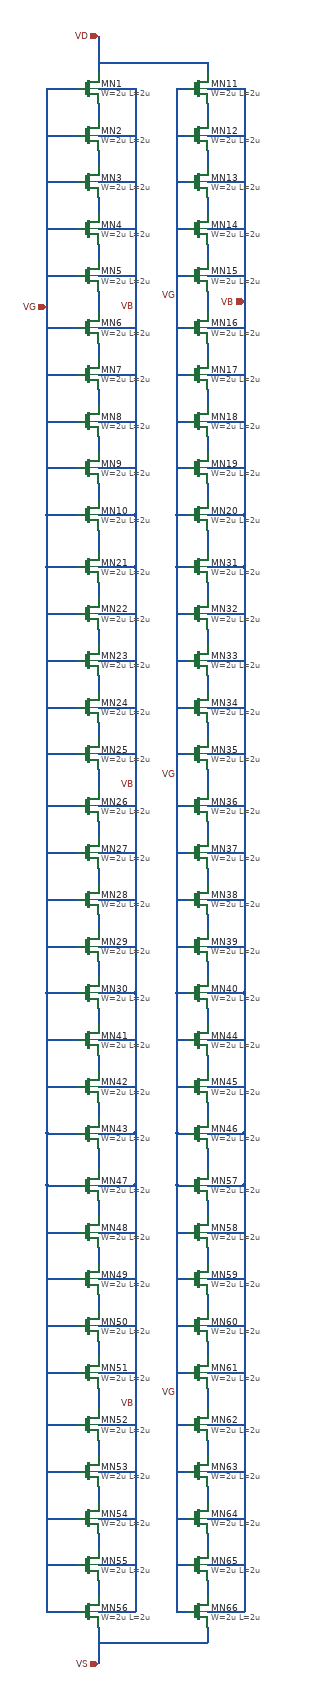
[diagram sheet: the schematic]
v {xschem version=3.4.5 file_version=1.2
}
G {}
K {}
V {}
S {}
E {}
N 0 30 0 60 {
lab=#net1}
N 0 120 0 150 {
lab=#net2}
N 0 210 0 240 {
lab=#net3}
N 0 300 0 330 {
lab=#net4}
N 0 390 0 430 {
lab=#net5}
N 0 490 0 520 {
lab=#net6}
N 0 580 0 610 {
lab=#net7}
N 0 670 0 700 {
lab=#net8}
N 0 760 0 790 {
lab=#net9}
N 0 2960 0 3030 {
lab=VS}
N 0 820 70 820 {
lab=VB}
N 70 0 70 820 {
lab=VB}
N 0 0 70 0 {
lab=VB}
N 0 90 70 90 {
lab=VB}
N 0 180 70 180 {
lab=VB}
N 0 270 70 270 {
lab=VB}
N 0 360 70 360 {
lab=VB}
N 0 460 70 460 {
lab=VB}
N 0 550 70 550 {
lab=VB}
N 0 640 70 640 {
lab=VB}
N 0 730 70 730 {
lab=VB}
N -100 0 -40 0 {
lab=VG}
N -100 0 -100 820 {
lab=VG}
N -100 820 -40 820 {
lab=VG}
N -100 730 -40 730 {
lab=VG}
N -100 640 -40 640 {
lab=VG}
N -100 550 -40 550 {
lab=VG}
N -100 460 -40 460 {
lab=VG}
N -100 360 -40 360 {
lab=VG}
N -100 270 -40 270 {
lab=VG}
N -100 180 -40 180 {
lab=VG}
N -100 90 -40 90 {
lab=VG}
N 0 -100 0 -30 {
lab=VD}
N 210 30 210 60 {
lab=#net10}
N 210 120 210 150 {
lab=#net11}
N 210 210 210 240 {
lab=#net12}
N 210 300 210 330 {
lab=#net13}
N 210 390 210 430 {
lab=#net14}
N 210 490 210 520 {
lab=#net15}
N 210 580 210 610 {
lab=#net16}
N 210 670 210 700 {
lab=#net17}
N 210 760 210 790 {
lab=#net18}
N 210 820 280 820 {
lab=VB}
N 280 0 280 820 {
lab=VB}
N 210 0 280 0 {
lab=VB}
N 210 90 280 90 {
lab=VB}
N 210 180 280 180 {
lab=VB}
N 210 270 280 270 {
lab=VB}
N 210 360 280 360 {
lab=VB}
N 210 460 280 460 {
lab=VB}
N 210 550 280 550 {
lab=VB}
N 210 640 280 640 {
lab=VB}
N 210 730 280 730 {
lab=VB}
N 150 0 170 0 {
lab=VG}
N 150 0 150 820 {
lab=VG}
N 150 820 170 820 {
lab=VG}
N 150 730 170 730 {
lab=VG}
N 150 640 170 640 {
lab=VG}
N 150 550 170 550 {
lab=VG}
N 150 460 170 460 {
lab=VG}
N 150 360 170 360 {
lab=VG}
N 150 270 170 270 {
lab=VG}
N 150 180 170 180 {
lab=VG}
N 150 90 170 90 {
lab=VG}
N 210 -50 210 -30 {
lab=VD}
N 0 -50 210 -50 {
lab=VD}
N 0 950 0 980 {
lab=#net19}
N 0 1040 0 1070 {
lab=#net20}
N 0 1130 0 1160 {
lab=#net21}
N 0 1220 0 1250 {
lab=#net22}
N 0 1310 0 1350 {
lab=#net23}
N 0 1410 0 1440 {
lab=#net24}
N 0 1500 0 1530 {
lab=#net25}
N 0 1590 0 1620 {
lab=#net26}
N 0 1680 0 1710 {
lab=#net27}
N 0 1740 70 1740 {
lab=VB}
N 70 920 70 1740 {
lab=VB}
N 0 920 70 920 {
lab=VB}
N 0 1010 70 1010 {
lab=VB}
N 0 1100 70 1100 {
lab=VB}
N 0 1190 70 1190 {
lab=VB}
N 0 1280 70 1280 {
lab=VB}
N 0 1380 70 1380 {
lab=VB}
N 0 1470 70 1470 {
lab=VB}
N 0 1560 70 1560 {
lab=VB}
N 0 1650 70 1650 {
lab=VB}
N -100 920 -40 920 {
lab=VG}
N -100 920 -100 1740 {
lab=VG}
N -100 1740 -40 1740 {
lab=VG}
N -100 1650 -40 1650 {
lab=VG}
N -100 1560 -40 1560 {
lab=VG}
N -100 1470 -40 1470 {
lab=VG}
N -100 1380 -40 1380 {
lab=VG}
N -100 1280 -40 1280 {
lab=VG}
N -100 1190 -40 1190 {
lab=VG}
N -100 1100 -40 1100 {
lab=VG}
N -100 1010 -40 1010 {
lab=VG}
N 210 950 210 980 {
lab=#net28}
N 210 1040 210 1070 {
lab=#net29}
N 210 1130 210 1160 {
lab=#net30}
N 210 1220 210 1250 {
lab=#net31}
N 210 1310 210 1350 {
lab=#net32}
N 210 1410 210 1440 {
lab=#net33}
N 210 1500 210 1530 {
lab=#net34}
N 210 1590 210 1620 {
lab=#net35}
N 210 1680 210 1710 {
lab=#net36}
N 210 1740 280 1740 {
lab=VB}
N 280 920 280 1740 {
lab=VB}
N 210 920 280 920 {
lab=VB}
N 210 1010 280 1010 {
lab=VB}
N 210 1100 280 1100 {
lab=VB}
N 210 1190 280 1190 {
lab=VB}
N 210 1280 280 1280 {
lab=VB}
N 210 1380 280 1380 {
lab=VB}
N 210 1470 280 1470 {
lab=VB}
N 210 1560 280 1560 {
lab=VB}
N 210 1650 280 1650 {
lab=VB}
N 150 920 170 920 {
lab=VG}
N 150 920 150 1740 {
lab=VG}
N 150 1740 170 1740 {
lab=VG}
N 150 1650 170 1650 {
lab=VG}
N 150 1560 170 1560 {
lab=VG}
N 150 1470 170 1470 {
lab=VG}
N 150 1380 170 1380 {
lab=VG}
N 150 1280 170 1280 {
lab=VG}
N 150 1190 170 1190 {
lab=VG}
N 150 1100 170 1100 {
lab=VG}
N 150 1010 170 1010 {
lab=VG}
N 0 850 0 890 {
lab=#net37}
N 210 850 210 890 {
lab=#net38}
N 280 830 280 920 {
lab=VB}
N 280 820 280 830 {
lab=VB}
N 150 820 150 920 {
lab=VG}
N 70 820 70 920 {
lab=VB}
N -100 820 -100 920 {
lab=VG}
N 210 2960 210 2990 {
lab=VS}
N 0 2990 210 2990 {
lab=VS}
N 0 1770 0 1800 {
lab=#net7}
N 0 1860 0 1890 {
lab=#net8}
N 0 1950 0 1980 {
lab=#net9}
N 0 2010 70 2010 {
lab=VB}
N 0 1830 70 1830 {
lab=VB}
N 0 1920 70 1920 {
lab=VB}
N -100 2010 -40 2010 {
lab=VG}
N -100 1920 -40 1920 {
lab=VG}
N -100 1830 -40 1830 {
lab=VG}
N 210 1770 210 1800 {
lab=#net16}
N 210 1860 210 1890 {
lab=#net17}
N 210 1950 210 1980 {
lab=#net18}
N 210 2010 280 2010 {
lab=VB}
N 210 1830 280 1830 {
lab=VB}
N 210 1920 280 1920 {
lab=VB}
N 150 2010 170 2010 {
lab=VG}
N 150 1920 170 1920 {
lab=VG}
N 150 1830 170 1830 {
lab=VG}
N 0 2140 0 2170 {
lab=#net19}
N 0 2230 0 2260 {
lab=#net20}
N 0 2320 0 2350 {
lab=#net21}
N 0 2410 0 2440 {
lab=#net22}
N 0 2500 0 2540 {
lab=#net23}
N 0 2600 0 2630 {
lab=#net24}
N 0 2690 0 2720 {
lab=#net25}
N 0 2780 0 2810 {
lab=#net26}
N 0 2870 0 2900 {
lab=#net27}
N 0 2930 70 2930 {
lab=VB}
N 70 2110 70 2930 {
lab=VB}
N 0 2110 70 2110 {
lab=VB}
N 0 2200 70 2200 {
lab=VB}
N 0 2290 70 2290 {
lab=VB}
N 0 2380 70 2380 {
lab=VB}
N 0 2470 70 2470 {
lab=VB}
N 0 2570 70 2570 {
lab=VB}
N 0 2660 70 2660 {
lab=VB}
N 0 2750 70 2750 {
lab=VB}
N 0 2840 70 2840 {
lab=VB}
N -100 2110 -40 2110 {
lab=VG}
N -100 2110 -100 2930 {
lab=VG}
N -100 2930 -40 2930 {
lab=VG}
N -100 2840 -40 2840 {
lab=VG}
N -100 2750 -40 2750 {
lab=VG}
N -100 2660 -40 2660 {
lab=VG}
N -100 2570 -40 2570 {
lab=VG}
N -100 2470 -40 2470 {
lab=VG}
N -100 2380 -40 2380 {
lab=VG}
N -100 2290 -40 2290 {
lab=VG}
N -100 2200 -40 2200 {
lab=VG}
N 210 2140 210 2170 {
lab=#net28}
N 210 2230 210 2260 {
lab=#net29}
N 210 2320 210 2350 {
lab=#net30}
N 210 2410 210 2440 {
lab=#net31}
N 210 2500 210 2540 {
lab=#net32}
N 210 2600 210 2630 {
lab=#net33}
N 210 2690 210 2720 {
lab=#net34}
N 210 2780 210 2810 {
lab=#net35}
N 210 2870 210 2900 {
lab=#net36}
N 210 2930 280 2930 {
lab=VB}
N 280 2110 280 2930 {
lab=VB}
N 210 2110 280 2110 {
lab=VB}
N 210 2200 280 2200 {
lab=VB}
N 210 2290 280 2290 {
lab=VB}
N 210 2380 280 2380 {
lab=VB}
N 210 2470 280 2470 {
lab=VB}
N 210 2570 280 2570 {
lab=VB}
N 210 2660 280 2660 {
lab=VB}
N 210 2750 280 2750 {
lab=VB}
N 210 2840 280 2840 {
lab=VB}
N 150 2110 170 2110 {
lab=VG}
N 150 2110 150 2930 {
lab=VG}
N 150 2930 170 2930 {
lab=VG}
N 150 2840 170 2840 {
lab=VG}
N 150 2750 170 2750 {
lab=VG}
N 150 2660 170 2660 {
lab=VG}
N 150 2570 170 2570 {
lab=VG}
N 150 2470 170 2470 {
lab=VG}
N 150 2380 170 2380 {
lab=VG}
N 150 2290 170 2290 {
lab=VG}
N 150 2200 170 2200 {
lab=VG}
N 0 2040 0 2080 {
lab=#net37}
N 210 2040 210 2080 {
lab=#net38}
N 280 2020 280 2110 {
lab=VB}
N 280 2010 280 2020 {
lab=VB}
N 150 2010 150 2110 {
lab=VG}
N 70 2010 70 2110 {
lab=VB}
N -100 2010 -100 2110 {
lab=VG}
N -100 1740 -100 2010 {}
N 70 1740 70 2010 {}
N 150 1740 150 2010 {}
N 280 1740 280 2000 {}
N 280 2000 280 2010 {}
C {symbols/nfet_03v3.sym} -20 0 0 0 {name=MN1
L=2u
W=2u
nf=1
m=1
ad="'int((nf+1)/2) * W/nf * 0.18u'"
pd="'2*int((nf+1)/2) * (W/nf + 0.18u)'"
as="'int((nf+2)/2) * W/nf * 0.18u'"
ps="'2*int((nf+2)/2) * (W/nf + 0.18u)'"
nrd="'0.18u / W'" nrs="'0.18u / W'"
sa=0 sb=0 sd=0
model=nfet_03v3
spiceprefix=X
}
C {symbols/nfet_03v3.sym} -20 90 0 0 {name=MN2
L=2u
W=2u
nf=1
m=1
ad="'int((nf+1)/2) * W/nf * 0.18u'"
pd="'2*int((nf+1)/2) * (W/nf + 0.18u)'"
as="'int((nf+2)/2) * W/nf * 0.18u'"
ps="'2*int((nf+2)/2) * (W/nf + 0.18u)'"
nrd="'0.18u / W'" nrs="'0.18u / W'"
sa=0 sb=0 sd=0
model=nfet_03v3
spiceprefix=X
}
C {symbols/nfet_03v3.sym} -20 180 0 0 {name=MN3
L=2u
W=2u
nf=1
m=1
ad="'int((nf+1)/2) * W/nf * 0.18u'"
pd="'2*int((nf+1)/2) * (W/nf + 0.18u)'"
as="'int((nf+2)/2) * W/nf * 0.18u'"
ps="'2*int((nf+2)/2) * (W/nf + 0.18u)'"
nrd="'0.18u / W'" nrs="'0.18u / W'"
sa=0 sb=0 sd=0
model=nfet_03v3
spiceprefix=X
}
C {symbols/nfet_03v3.sym} -20 270 0 0 {name=MN4
L=2u
W=2u
nf=1
m=1
ad="'int((nf+1)/2) * W/nf * 0.18u'"
pd="'2*int((nf+1)/2) * (W/nf + 0.18u)'"
as="'int((nf+2)/2) * W/nf * 0.18u'"
ps="'2*int((nf+2)/2) * (W/nf + 0.18u)'"
nrd="'0.18u / W'" nrs="'0.18u / W'"
sa=0 sb=0 sd=0
model=nfet_03v3
spiceprefix=X
}
C {symbols/nfet_03v3.sym} -20 360 0 0 {name=MN5
L=2u
W=2u
nf=1
m=1
ad="'int((nf+1)/2) * W/nf * 0.18u'"
pd="'2*int((nf+1)/2) * (W/nf + 0.18u)'"
as="'int((nf+2)/2) * W/nf * 0.18u'"
ps="'2*int((nf+2)/2) * (W/nf + 0.18u)'"
nrd="'0.18u / W'" nrs="'0.18u / W'"
sa=0 sb=0 sd=0
model=nfet_03v3
spiceprefix=X
}
C {symbols/nfet_03v3.sym} -20 460 0 0 {name=MN6
L=2u
W=2u
nf=1
m=1
ad="'int((nf+1)/2) * W/nf * 0.18u'"
pd="'2*int((nf+1)/2) * (W/nf + 0.18u)'"
as="'int((nf+2)/2) * W/nf * 0.18u'"
ps="'2*int((nf+2)/2) * (W/nf + 0.18u)'"
nrd="'0.18u / W'" nrs="'0.18u / W'"
sa=0 sb=0 sd=0
model=nfet_03v3
spiceprefix=X
}
C {symbols/nfet_03v3.sym} -20 550 0 0 {name=MN7
L=2u
W=2u
nf=1
m=1
ad="'int((nf+1)/2) * W/nf * 0.18u'"
pd="'2*int((nf+1)/2) * (W/nf + 0.18u)'"
as="'int((nf+2)/2) * W/nf * 0.18u'"
ps="'2*int((nf+2)/2) * (W/nf + 0.18u)'"
nrd="'0.18u / W'" nrs="'0.18u / W'"
sa=0 sb=0 sd=0
model=nfet_03v3
spiceprefix=X
}
C {symbols/nfet_03v3.sym} -20 640 0 0 {name=MN8
L=2u
W=2u
nf=1
m=1
ad="'int((nf+1)/2) * W/nf * 0.18u'"
pd="'2*int((nf+1)/2) * (W/nf + 0.18u)'"
as="'int((nf+2)/2) * W/nf * 0.18u'"
ps="'2*int((nf+2)/2) * (W/nf + 0.18u)'"
nrd="'0.18u / W'" nrs="'0.18u / W'"
sa=0 sb=0 sd=0
model=nfet_03v3
spiceprefix=X
}
C {symbols/nfet_03v3.sym} -20 730 0 0 {name=MN9
L=2u
W=2u
nf=1
m=1
ad="'int((nf+1)/2) * W/nf * 0.18u'"
pd="'2*int((nf+1)/2) * (W/nf + 0.18u)'"
as="'int((nf+2)/2) * W/nf * 0.18u'"
ps="'2*int((nf+2)/2) * (W/nf + 0.18u)'"
nrd="'0.18u / W'" nrs="'0.18u / W'"
sa=0 sb=0 sd=0
model=nfet_03v3
spiceprefix=X
}
C {symbols/nfet_03v3.sym} -20 820 0 0 {name=MN10
L=2u
W=2u
nf=1
m=1
ad="'int((nf+1)/2) * W/nf * 0.18u'"
pd="'2*int((nf+1)/2) * (W/nf + 0.18u)'"
as="'int((nf+2)/2) * W/nf * 0.18u'"
ps="'2*int((nf+2)/2) * (W/nf + 0.18u)'"
nrd="'0.18u / W'" nrs="'0.18u / W'"
sa=0 sb=0 sd=0
model=nfet_03v3
spiceprefix=X
}
C {devices/iopin.sym} 0 -100 3 0 {name=p1 lab=VD}
C {devices/iopin.sym} -100 420 2 0 {name=p3 lab=VG}
C {devices/iopin.sym} 0 3030 1 0 {name=p4 lab=VS}
C {symbols/nfet_03v3.sym} 190 0 0 0 {name=MN11
L=2u
W=2u
nf=1
m=1
ad="'int((nf+1)/2) * W/nf * 0.18u'"
pd="'2*int((nf+1)/2) * (W/nf + 0.18u)'"
as="'int((nf+2)/2) * W/nf * 0.18u'"
ps="'2*int((nf+2)/2) * (W/nf + 0.18u)'"
nrd="'0.18u / W'" nrs="'0.18u / W'"
sa=0 sb=0 sd=0
model=nfet_03v3
spiceprefix=X
}
C {symbols/nfet_03v3.sym} 190 90 0 0 {name=MN12
L=2u
W=2u
nf=1
m=1
ad="'int((nf+1)/2) * W/nf * 0.18u'"
pd="'2*int((nf+1)/2) * (W/nf + 0.18u)'"
as="'int((nf+2)/2) * W/nf * 0.18u'"
ps="'2*int((nf+2)/2) * (W/nf + 0.18u)'"
nrd="'0.18u / W'" nrs="'0.18u / W'"
sa=0 sb=0 sd=0
model=nfet_03v3
spiceprefix=X
}
C {symbols/nfet_03v3.sym} 190 180 0 0 {name=MN13
L=2u
W=2u
nf=1
m=1
ad="'int((nf+1)/2) * W/nf * 0.18u'"
pd="'2*int((nf+1)/2) * (W/nf + 0.18u)'"
as="'int((nf+2)/2) * W/nf * 0.18u'"
ps="'2*int((nf+2)/2) * (W/nf + 0.18u)'"
nrd="'0.18u / W'" nrs="'0.18u / W'"
sa=0 sb=0 sd=0
model=nfet_03v3
spiceprefix=X
}
C {symbols/nfet_03v3.sym} 190 270 0 0 {name=MN14
L=2u
W=2u
nf=1
m=1
ad="'int((nf+1)/2) * W/nf * 0.18u'"
pd="'2*int((nf+1)/2) * (W/nf + 0.18u)'"
as="'int((nf+2)/2) * W/nf * 0.18u'"
ps="'2*int((nf+2)/2) * (W/nf + 0.18u)'"
nrd="'0.18u / W'" nrs="'0.18u / W'"
sa=0 sb=0 sd=0
model=nfet_03v3
spiceprefix=X
}
C {symbols/nfet_03v3.sym} 190 360 0 0 {name=MN15
L=2u
W=2u
nf=1
m=1
ad="'int((nf+1)/2) * W/nf * 0.18u'"
pd="'2*int((nf+1)/2) * (W/nf + 0.18u)'"
as="'int((nf+2)/2) * W/nf * 0.18u'"
ps="'2*int((nf+2)/2) * (W/nf + 0.18u)'"
nrd="'0.18u / W'" nrs="'0.18u / W'"
sa=0 sb=0 sd=0
model=nfet_03v3
spiceprefix=X
}
C {symbols/nfet_03v3.sym} 190 460 0 0 {name=MN16
L=2u
W=2u
nf=1
m=1
ad="'int((nf+1)/2) * W/nf * 0.18u'"
pd="'2*int((nf+1)/2) * (W/nf + 0.18u)'"
as="'int((nf+2)/2) * W/nf * 0.18u'"
ps="'2*int((nf+2)/2) * (W/nf + 0.18u)'"
nrd="'0.18u / W'" nrs="'0.18u / W'"
sa=0 sb=0 sd=0
model=nfet_03v3
spiceprefix=X
}
C {symbols/nfet_03v3.sym} 190 550 0 0 {name=MN17
L=2u
W=2u
nf=1
m=1
ad="'int((nf+1)/2) * W/nf * 0.18u'"
pd="'2*int((nf+1)/2) * (W/nf + 0.18u)'"
as="'int((nf+2)/2) * W/nf * 0.18u'"
ps="'2*int((nf+2)/2) * (W/nf + 0.18u)'"
nrd="'0.18u / W'" nrs="'0.18u / W'"
sa=0 sb=0 sd=0
model=nfet_03v3
spiceprefix=X
}
C {symbols/nfet_03v3.sym} 190 640 0 0 {name=MN18
L=2u
W=2u
nf=1
m=1
ad="'int((nf+1)/2) * W/nf * 0.18u'"
pd="'2*int((nf+1)/2) * (W/nf + 0.18u)'"
as="'int((nf+2)/2) * W/nf * 0.18u'"
ps="'2*int((nf+2)/2) * (W/nf + 0.18u)'"
nrd="'0.18u / W'" nrs="'0.18u / W'"
sa=0 sb=0 sd=0
model=nfet_03v3
spiceprefix=X
}
C {symbols/nfet_03v3.sym} 190 730 0 0 {name=MN19
L=2u
W=2u
nf=1
m=1
ad="'int((nf+1)/2) * W/nf * 0.18u'"
pd="'2*int((nf+1)/2) * (W/nf + 0.18u)'"
as="'int((nf+2)/2) * W/nf * 0.18u'"
ps="'2*int((nf+2)/2) * (W/nf + 0.18u)'"
nrd="'0.18u / W'" nrs="'0.18u / W'"
sa=0 sb=0 sd=0
model=nfet_03v3
spiceprefix=X
}
C {symbols/nfet_03v3.sym} 190 820 0 0 {name=MN20
L=2u
W=2u
nf=1
m=1
ad="'int((nf+1)/2) * W/nf * 0.18u'"
pd="'2*int((nf+1)/2) * (W/nf + 0.18u)'"
as="'int((nf+2)/2) * W/nf * 0.18u'"
ps="'2*int((nf+2)/2) * (W/nf + 0.18u)'"
nrd="'0.18u / W'" nrs="'0.18u / W'"
sa=0 sb=0 sd=0
model=nfet_03v3
spiceprefix=X
}
C {devices/iopin.sym} 280 410 0 0 {name=p5 lab=VB}
C {devices/lab_wire.sym} 70 420 0 0 {name=p26 sig_type=std_logic lab=VB}
C {devices/lab_wire.sym} 150 400 0 0 {name=p2 sig_type=std_logic lab=VG}
C {symbols/nfet_03v3.sym} -20 920 0 0 {name=MN21
L=2u
W=2u
nf=1
m=1
ad="'int((nf+1)/2) * W/nf * 0.18u'"
pd="'2*int((nf+1)/2) * (W/nf + 0.18u)'"
as="'int((nf+2)/2) * W/nf * 0.18u'"
ps="'2*int((nf+2)/2) * (W/nf + 0.18u)'"
nrd="'0.18u / W'" nrs="'0.18u / W'"
sa=0 sb=0 sd=0
model=nfet_03v3
spiceprefix=X
}
C {symbols/nfet_03v3.sym} -20 1010 0 0 {name=MN22
L=2u
W=2u
nf=1
m=1
ad="'int((nf+1)/2) * W/nf * 0.18u'"
pd="'2*int((nf+1)/2) * (W/nf + 0.18u)'"
as="'int((nf+2)/2) * W/nf * 0.18u'"
ps="'2*int((nf+2)/2) * (W/nf + 0.18u)'"
nrd="'0.18u / W'" nrs="'0.18u / W'"
sa=0 sb=0 sd=0
model=nfet_03v3
spiceprefix=X
}
C {symbols/nfet_03v3.sym} -20 1100 0 0 {name=MN23
L=2u
W=2u
nf=1
m=1
ad="'int((nf+1)/2) * W/nf * 0.18u'"
pd="'2*int((nf+1)/2) * (W/nf + 0.18u)'"
as="'int((nf+2)/2) * W/nf * 0.18u'"
ps="'2*int((nf+2)/2) * (W/nf + 0.18u)'"
nrd="'0.18u / W'" nrs="'0.18u / W'"
sa=0 sb=0 sd=0
model=nfet_03v3
spiceprefix=X
}
C {symbols/nfet_03v3.sym} -20 1190 0 0 {name=MN24
L=2u
W=2u
nf=1
m=1
ad="'int((nf+1)/2) * W/nf * 0.18u'"
pd="'2*int((nf+1)/2) * (W/nf + 0.18u)'"
as="'int((nf+2)/2) * W/nf * 0.18u'"
ps="'2*int((nf+2)/2) * (W/nf + 0.18u)'"
nrd="'0.18u / W'" nrs="'0.18u / W'"
sa=0 sb=0 sd=0
model=nfet_03v3
spiceprefix=X
}
C {symbols/nfet_03v3.sym} -20 1280 0 0 {name=MN25
L=2u
W=2u
nf=1
m=1
ad="'int((nf+1)/2) * W/nf * 0.18u'"
pd="'2*int((nf+1)/2) * (W/nf + 0.18u)'"
as="'int((nf+2)/2) * W/nf * 0.18u'"
ps="'2*int((nf+2)/2) * (W/nf + 0.18u)'"
nrd="'0.18u / W'" nrs="'0.18u / W'"
sa=0 sb=0 sd=0
model=nfet_03v3
spiceprefix=X
}
C {symbols/nfet_03v3.sym} -20 1380 0 0 {name=MN26
L=2u
W=2u
nf=1
m=1
ad="'int((nf+1)/2) * W/nf * 0.18u'"
pd="'2*int((nf+1)/2) * (W/nf + 0.18u)'"
as="'int((nf+2)/2) * W/nf * 0.18u'"
ps="'2*int((nf+2)/2) * (W/nf + 0.18u)'"
nrd="'0.18u / W'" nrs="'0.18u / W'"
sa=0 sb=0 sd=0
model=nfet_03v3
spiceprefix=X
}
C {symbols/nfet_03v3.sym} -20 1470 0 0 {name=MN27
L=2u
W=2u
nf=1
m=1
ad="'int((nf+1)/2) * W/nf * 0.18u'"
pd="'2*int((nf+1)/2) * (W/nf + 0.18u)'"
as="'int((nf+2)/2) * W/nf * 0.18u'"
ps="'2*int((nf+2)/2) * (W/nf + 0.18u)'"
nrd="'0.18u / W'" nrs="'0.18u / W'"
sa=0 sb=0 sd=0
model=nfet_03v3
spiceprefix=X
}
C {symbols/nfet_03v3.sym} -20 1560 0 0 {name=MN28
L=2u
W=2u
nf=1
m=1
ad="'int((nf+1)/2) * W/nf * 0.18u'"
pd="'2*int((nf+1)/2) * (W/nf + 0.18u)'"
as="'int((nf+2)/2) * W/nf * 0.18u'"
ps="'2*int((nf+2)/2) * (W/nf + 0.18u)'"
nrd="'0.18u / W'" nrs="'0.18u / W'"
sa=0 sb=0 sd=0
model=nfet_03v3
spiceprefix=X
}
C {symbols/nfet_03v3.sym} -20 1650 0 0 {name=MN29
L=2u
W=2u
nf=1
m=1
ad="'int((nf+1)/2) * W/nf * 0.18u'"
pd="'2*int((nf+1)/2) * (W/nf + 0.18u)'"
as="'int((nf+2)/2) * W/nf * 0.18u'"
ps="'2*int((nf+2)/2) * (W/nf + 0.18u)'"
nrd="'0.18u / W'" nrs="'0.18u / W'"
sa=0 sb=0 sd=0
model=nfet_03v3
spiceprefix=X
}
C {symbols/nfet_03v3.sym} -20 1740 0 0 {name=MN30
L=2u
W=2u
nf=1
m=1
ad="'int((nf+1)/2) * W/nf * 0.18u'"
pd="'2*int((nf+1)/2) * (W/nf + 0.18u)'"
as="'int((nf+2)/2) * W/nf * 0.18u'"
ps="'2*int((nf+2)/2) * (W/nf + 0.18u)'"
nrd="'0.18u / W'" nrs="'0.18u / W'"
sa=0 sb=0 sd=0
model=nfet_03v3
spiceprefix=X
}
C {symbols/nfet_03v3.sym} 190 920 0 0 {name=MN31
L=2u
W=2u
nf=1
m=1
ad="'int((nf+1)/2) * W/nf * 0.18u'"
pd="'2*int((nf+1)/2) * (W/nf + 0.18u)'"
as="'int((nf+2)/2) * W/nf * 0.18u'"
ps="'2*int((nf+2)/2) * (W/nf + 0.18u)'"
nrd="'0.18u / W'" nrs="'0.18u / W'"
sa=0 sb=0 sd=0
model=nfet_03v3
spiceprefix=X
}
C {symbols/nfet_03v3.sym} 190 1010 0 0 {name=MN32
L=2u
W=2u
nf=1
m=1
ad="'int((nf+1)/2) * W/nf * 0.18u'"
pd="'2*int((nf+1)/2) * (W/nf + 0.18u)'"
as="'int((nf+2)/2) * W/nf * 0.18u'"
ps="'2*int((nf+2)/2) * (W/nf + 0.18u)'"
nrd="'0.18u / W'" nrs="'0.18u / W'"
sa=0 sb=0 sd=0
model=nfet_03v3
spiceprefix=X
}
C {symbols/nfet_03v3.sym} 190 1100 0 0 {name=MN33
L=2u
W=2u
nf=1
m=1
ad="'int((nf+1)/2) * W/nf * 0.18u'"
pd="'2*int((nf+1)/2) * (W/nf + 0.18u)'"
as="'int((nf+2)/2) * W/nf * 0.18u'"
ps="'2*int((nf+2)/2) * (W/nf + 0.18u)'"
nrd="'0.18u / W'" nrs="'0.18u / W'"
sa=0 sb=0 sd=0
model=nfet_03v3
spiceprefix=X
}
C {symbols/nfet_03v3.sym} 190 1190 0 0 {name=MN34
L=2u
W=2u
nf=1
m=1
ad="'int((nf+1)/2) * W/nf * 0.18u'"
pd="'2*int((nf+1)/2) * (W/nf + 0.18u)'"
as="'int((nf+2)/2) * W/nf * 0.18u'"
ps="'2*int((nf+2)/2) * (W/nf + 0.18u)'"
nrd="'0.18u / W'" nrs="'0.18u / W'"
sa=0 sb=0 sd=0
model=nfet_03v3
spiceprefix=X
}
C {symbols/nfet_03v3.sym} 190 1280 0 0 {name=MN35
L=2u
W=2u
nf=1
m=1
ad="'int((nf+1)/2) * W/nf * 0.18u'"
pd="'2*int((nf+1)/2) * (W/nf + 0.18u)'"
as="'int((nf+2)/2) * W/nf * 0.18u'"
ps="'2*int((nf+2)/2) * (W/nf + 0.18u)'"
nrd="'0.18u / W'" nrs="'0.18u / W'"
sa=0 sb=0 sd=0
model=nfet_03v3
spiceprefix=X
}
C {symbols/nfet_03v3.sym} 190 1380 0 0 {name=MN36
L=2u
W=2u
nf=1
m=1
ad="'int((nf+1)/2) * W/nf * 0.18u'"
pd="'2*int((nf+1)/2) * (W/nf + 0.18u)'"
as="'int((nf+2)/2) * W/nf * 0.18u'"
ps="'2*int((nf+2)/2) * (W/nf + 0.18u)'"
nrd="'0.18u / W'" nrs="'0.18u / W'"
sa=0 sb=0 sd=0
model=nfet_03v3
spiceprefix=X
}
C {symbols/nfet_03v3.sym} 190 1470 0 0 {name=MN37
L=2u
W=2u
nf=1
m=1
ad="'int((nf+1)/2) * W/nf * 0.18u'"
pd="'2*int((nf+1)/2) * (W/nf + 0.18u)'"
as="'int((nf+2)/2) * W/nf * 0.18u'"
ps="'2*int((nf+2)/2) * (W/nf + 0.18u)'"
nrd="'0.18u / W'" nrs="'0.18u / W'"
sa=0 sb=0 sd=0
model=nfet_03v3
spiceprefix=X
}
C {symbols/nfet_03v3.sym} 190 1560 0 0 {name=MN38
L=2u
W=2u
nf=1
m=1
ad="'int((nf+1)/2) * W/nf * 0.18u'"
pd="'2*int((nf+1)/2) * (W/nf + 0.18u)'"
as="'int((nf+2)/2) * W/nf * 0.18u'"
ps="'2*int((nf+2)/2) * (W/nf + 0.18u)'"
nrd="'0.18u / W'" nrs="'0.18u / W'"
sa=0 sb=0 sd=0
model=nfet_03v3
spiceprefix=X
}
C {symbols/nfet_03v3.sym} 190 1650 0 0 {name=MN39
L=2u
W=2u
nf=1
m=1
ad="'int((nf+1)/2) * W/nf * 0.18u'"
pd="'2*int((nf+1)/2) * (W/nf + 0.18u)'"
as="'int((nf+2)/2) * W/nf * 0.18u'"
ps="'2*int((nf+2)/2) * (W/nf + 0.18u)'"
nrd="'0.18u / W'" nrs="'0.18u / W'"
sa=0 sb=0 sd=0
model=nfet_03v3
spiceprefix=X
}
C {symbols/nfet_03v3.sym} 190 1740 0 0 {name=MN40
L=2u
W=2u
nf=1
m=1
ad="'int((nf+1)/2) * W/nf * 0.18u'"
pd="'2*int((nf+1)/2) * (W/nf + 0.18u)'"
as="'int((nf+2)/2) * W/nf * 0.18u'"
ps="'2*int((nf+2)/2) * (W/nf + 0.18u)'"
nrd="'0.18u / W'" nrs="'0.18u / W'"
sa=0 sb=0 sd=0
model=nfet_03v3
spiceprefix=X
}
C {devices/lab_wire.sym} 70 1340 0 0 {name=p8 sig_type=std_logic lab=VB}
C {devices/lab_wire.sym} 150 1320 0 0 {name=p9 sig_type=std_logic lab=VG}
C {symbols/nfet_03v3.sym} -20 1830 0 0 {name=MN41
L=2u
W=2u
nf=1
m=1
ad="'int((nf+1)/2) * W/nf * 0.18u'"
pd="'2*int((nf+1)/2) * (W/nf + 0.18u)'"
as="'int((nf+2)/2) * W/nf * 0.18u'"
ps="'2*int((nf+2)/2) * (W/nf + 0.18u)'"
nrd="'0.18u / W'" nrs="'0.18u / W'"
sa=0 sb=0 sd=0
model=nfet_03v3
spiceprefix=X
}
C {symbols/nfet_03v3.sym} -20 1920 0 0 {name=MN42
L=2u
W=2u
nf=1
m=1
ad="'int((nf+1)/2) * W/nf * 0.18u'"
pd="'2*int((nf+1)/2) * (W/nf + 0.18u)'"
as="'int((nf+2)/2) * W/nf * 0.18u'"
ps="'2*int((nf+2)/2) * (W/nf + 0.18u)'"
nrd="'0.18u / W'" nrs="'0.18u / W'"
sa=0 sb=0 sd=0
model=nfet_03v3
spiceprefix=X
}
C {symbols/nfet_03v3.sym} -20 2010 0 0 {name=MN43
L=2u
W=2u
nf=1
m=1
ad="'int((nf+1)/2) * W/nf * 0.18u'"
pd="'2*int((nf+1)/2) * (W/nf + 0.18u)'"
as="'int((nf+2)/2) * W/nf * 0.18u'"
ps="'2*int((nf+2)/2) * (W/nf + 0.18u)'"
nrd="'0.18u / W'" nrs="'0.18u / W'"
sa=0 sb=0 sd=0
model=nfet_03v3
spiceprefix=X
}
C {symbols/nfet_03v3.sym} 190 1830 0 0 {name=MN44
L=2u
W=2u
nf=1
m=1
ad="'int((nf+1)/2) * W/nf * 0.18u'"
pd="'2*int((nf+1)/2) * (W/nf + 0.18u)'"
as="'int((nf+2)/2) * W/nf * 0.18u'"
ps="'2*int((nf+2)/2) * (W/nf + 0.18u)'"
nrd="'0.18u / W'" nrs="'0.18u / W'"
sa=0 sb=0 sd=0
model=nfet_03v3
spiceprefix=X
}
C {symbols/nfet_03v3.sym} 190 1920 0 0 {name=MN45
L=2u
W=2u
nf=1
m=1
ad="'int((nf+1)/2) * W/nf * 0.18u'"
pd="'2*int((nf+1)/2) * (W/nf + 0.18u)'"
as="'int((nf+2)/2) * W/nf * 0.18u'"
ps="'2*int((nf+2)/2) * (W/nf + 0.18u)'"
nrd="'0.18u / W'" nrs="'0.18u / W'"
sa=0 sb=0 sd=0
model=nfet_03v3
spiceprefix=X
}
C {symbols/nfet_03v3.sym} 190 2010 0 0 {name=MN46
L=2u
W=2u
nf=1
m=1
ad="'int((nf+1)/2) * W/nf * 0.18u'"
pd="'2*int((nf+1)/2) * (W/nf + 0.18u)'"
as="'int((nf+2)/2) * W/nf * 0.18u'"
ps="'2*int((nf+2)/2) * (W/nf + 0.18u)'"
nrd="'0.18u / W'" nrs="'0.18u / W'"
sa=0 sb=0 sd=0
model=nfet_03v3
spiceprefix=X
}
C {symbols/nfet_03v3.sym} -20 2110 0 0 {name=MN47
L=2u
W=2u
nf=1
m=1
ad="'int((nf+1)/2) * W/nf * 0.18u'"
pd="'2*int((nf+1)/2) * (W/nf + 0.18u)'"
as="'int((nf+2)/2) * W/nf * 0.18u'"
ps="'2*int((nf+2)/2) * (W/nf + 0.18u)'"
nrd="'0.18u / W'" nrs="'0.18u / W'"
sa=0 sb=0 sd=0
model=nfet_03v3
spiceprefix=X
}
C {symbols/nfet_03v3.sym} -20 2200 0 0 {name=MN48
L=2u
W=2u
nf=1
m=1
ad="'int((nf+1)/2) * W/nf * 0.18u'"
pd="'2*int((nf+1)/2) * (W/nf + 0.18u)'"
as="'int((nf+2)/2) * W/nf * 0.18u'"
ps="'2*int((nf+2)/2) * (W/nf + 0.18u)'"
nrd="'0.18u / W'" nrs="'0.18u / W'"
sa=0 sb=0 sd=0
model=nfet_03v3
spiceprefix=X
}
C {symbols/nfet_03v3.sym} -20 2290 0 0 {name=MN49
L=2u
W=2u
nf=1
m=1
ad="'int((nf+1)/2) * W/nf * 0.18u'"
pd="'2*int((nf+1)/2) * (W/nf + 0.18u)'"
as="'int((nf+2)/2) * W/nf * 0.18u'"
ps="'2*int((nf+2)/2) * (W/nf + 0.18u)'"
nrd="'0.18u / W'" nrs="'0.18u / W'"
sa=0 sb=0 sd=0
model=nfet_03v3
spiceprefix=X
}
C {symbols/nfet_03v3.sym} -20 2380 0 0 {name=MN50
L=2u
W=2u
nf=1
m=1
ad="'int((nf+1)/2) * W/nf * 0.18u'"
pd="'2*int((nf+1)/2) * (W/nf + 0.18u)'"
as="'int((nf+2)/2) * W/nf * 0.18u'"
ps="'2*int((nf+2)/2) * (W/nf + 0.18u)'"
nrd="'0.18u / W'" nrs="'0.18u / W'"
sa=0 sb=0 sd=0
model=nfet_03v3
spiceprefix=X
}
C {symbols/nfet_03v3.sym} -20 2470 0 0 {name=MN51
L=2u
W=2u
nf=1
m=1
ad="'int((nf+1)/2) * W/nf * 0.18u'"
pd="'2*int((nf+1)/2) * (W/nf + 0.18u)'"
as="'int((nf+2)/2) * W/nf * 0.18u'"
ps="'2*int((nf+2)/2) * (W/nf + 0.18u)'"
nrd="'0.18u / W'" nrs="'0.18u / W'"
sa=0 sb=0 sd=0
model=nfet_03v3
spiceprefix=X
}
C {symbols/nfet_03v3.sym} -20 2570 0 0 {name=MN52
L=2u
W=2u
nf=1
m=1
ad="'int((nf+1)/2) * W/nf * 0.18u'"
pd="'2*int((nf+1)/2) * (W/nf + 0.18u)'"
as="'int((nf+2)/2) * W/nf * 0.18u'"
ps="'2*int((nf+2)/2) * (W/nf + 0.18u)'"
nrd="'0.18u / W'" nrs="'0.18u / W'"
sa=0 sb=0 sd=0
model=nfet_03v3
spiceprefix=X
}
C {symbols/nfet_03v3.sym} -20 2660 0 0 {name=MN53
L=2u
W=2u
nf=1
m=1
ad="'int((nf+1)/2) * W/nf * 0.18u'"
pd="'2*int((nf+1)/2) * (W/nf + 0.18u)'"
as="'int((nf+2)/2) * W/nf * 0.18u'"
ps="'2*int((nf+2)/2) * (W/nf + 0.18u)'"
nrd="'0.18u / W'" nrs="'0.18u / W'"
sa=0 sb=0 sd=0
model=nfet_03v3
spiceprefix=X
}
C {symbols/nfet_03v3.sym} -20 2750 0 0 {name=MN54
L=2u
W=2u
nf=1
m=1
ad="'int((nf+1)/2) * W/nf * 0.18u'"
pd="'2*int((nf+1)/2) * (W/nf + 0.18u)'"
as="'int((nf+2)/2) * W/nf * 0.18u'"
ps="'2*int((nf+2)/2) * (W/nf + 0.18u)'"
nrd="'0.18u / W'" nrs="'0.18u / W'"
sa=0 sb=0 sd=0
model=nfet_03v3
spiceprefix=X
}
C {symbols/nfet_03v3.sym} -20 2840 0 0 {name=MN55
L=2u
W=2u
nf=1
m=1
ad="'int((nf+1)/2) * W/nf * 0.18u'"
pd="'2*int((nf+1)/2) * (W/nf + 0.18u)'"
as="'int((nf+2)/2) * W/nf * 0.18u'"
ps="'2*int((nf+2)/2) * (W/nf + 0.18u)'"
nrd="'0.18u / W'" nrs="'0.18u / W'"
sa=0 sb=0 sd=0
model=nfet_03v3
spiceprefix=X
}
C {symbols/nfet_03v3.sym} -20 2930 0 0 {name=MN56
L=2u
W=2u
nf=1
m=1
ad="'int((nf+1)/2) * W/nf * 0.18u'"
pd="'2*int((nf+1)/2) * (W/nf + 0.18u)'"
as="'int((nf+2)/2) * W/nf * 0.18u'"
ps="'2*int((nf+2)/2) * (W/nf + 0.18u)'"
nrd="'0.18u / W'" nrs="'0.18u / W'"
sa=0 sb=0 sd=0
model=nfet_03v3
spiceprefix=X
}
C {symbols/nfet_03v3.sym} 190 2110 0 0 {name=MN57
L=2u
W=2u
nf=1
m=1
ad="'int((nf+1)/2) * W/nf * 0.18u'"
pd="'2*int((nf+1)/2) * (W/nf + 0.18u)'"
as="'int((nf+2)/2) * W/nf * 0.18u'"
ps="'2*int((nf+2)/2) * (W/nf + 0.18u)'"
nrd="'0.18u / W'" nrs="'0.18u / W'"
sa=0 sb=0 sd=0
model=nfet_03v3
spiceprefix=X
}
C {symbols/nfet_03v3.sym} 190 2200 0 0 {name=MN58
L=2u
W=2u
nf=1
m=1
ad="'int((nf+1)/2) * W/nf * 0.18u'"
pd="'2*int((nf+1)/2) * (W/nf + 0.18u)'"
as="'int((nf+2)/2) * W/nf * 0.18u'"
ps="'2*int((nf+2)/2) * (W/nf + 0.18u)'"
nrd="'0.18u / W'" nrs="'0.18u / W'"
sa=0 sb=0 sd=0
model=nfet_03v3
spiceprefix=X
}
C {symbols/nfet_03v3.sym} 190 2290 0 0 {name=MN59
L=2u
W=2u
nf=1
m=1
ad="'int((nf+1)/2) * W/nf * 0.18u'"
pd="'2*int((nf+1)/2) * (W/nf + 0.18u)'"
as="'int((nf+2)/2) * W/nf * 0.18u'"
ps="'2*int((nf+2)/2) * (W/nf + 0.18u)'"
nrd="'0.18u / W'" nrs="'0.18u / W'"
sa=0 sb=0 sd=0
model=nfet_03v3
spiceprefix=X
}
C {symbols/nfet_03v3.sym} 190 2380 0 0 {name=MN60
L=2u
W=2u
nf=1
m=1
ad="'int((nf+1)/2) * W/nf * 0.18u'"
pd="'2*int((nf+1)/2) * (W/nf + 0.18u)'"
as="'int((nf+2)/2) * W/nf * 0.18u'"
ps="'2*int((nf+2)/2) * (W/nf + 0.18u)'"
nrd="'0.18u / W'" nrs="'0.18u / W'"
sa=0 sb=0 sd=0
model=nfet_03v3
spiceprefix=X
}
C {symbols/nfet_03v3.sym} 190 2470 0 0 {name=MN61
L=2u
W=2u
nf=1
m=1
ad="'int((nf+1)/2) * W/nf * 0.18u'"
pd="'2*int((nf+1)/2) * (W/nf + 0.18u)'"
as="'int((nf+2)/2) * W/nf * 0.18u'"
ps="'2*int((nf+2)/2) * (W/nf + 0.18u)'"
nrd="'0.18u / W'" nrs="'0.18u / W'"
sa=0 sb=0 sd=0
model=nfet_03v3
spiceprefix=X
}
C {symbols/nfet_03v3.sym} 190 2570 0 0 {name=MN62
L=2u
W=2u
nf=1
m=1
ad="'int((nf+1)/2) * W/nf * 0.18u'"
pd="'2*int((nf+1)/2) * (W/nf + 0.18u)'"
as="'int((nf+2)/2) * W/nf * 0.18u'"
ps="'2*int((nf+2)/2) * (W/nf + 0.18u)'"
nrd="'0.18u / W'" nrs="'0.18u / W'"
sa=0 sb=0 sd=0
model=nfet_03v3
spiceprefix=X
}
C {symbols/nfet_03v3.sym} 190 2660 0 0 {name=MN63
L=2u
W=2u
nf=1
m=1
ad="'int((nf+1)/2) * W/nf * 0.18u'"
pd="'2*int((nf+1)/2) * (W/nf + 0.18u)'"
as="'int((nf+2)/2) * W/nf * 0.18u'"
ps="'2*int((nf+2)/2) * (W/nf + 0.18u)'"
nrd="'0.18u / W'" nrs="'0.18u / W'"
sa=0 sb=0 sd=0
model=nfet_03v3
spiceprefix=X
}
C {symbols/nfet_03v3.sym} 190 2750 0 0 {name=MN64
L=2u
W=2u
nf=1
m=1
ad="'int((nf+1)/2) * W/nf * 0.18u'"
pd="'2*int((nf+1)/2) * (W/nf + 0.18u)'"
as="'int((nf+2)/2) * W/nf * 0.18u'"
ps="'2*int((nf+2)/2) * (W/nf + 0.18u)'"
nrd="'0.18u / W'" nrs="'0.18u / W'"
sa=0 sb=0 sd=0
model=nfet_03v3
spiceprefix=X
}
C {symbols/nfet_03v3.sym} 190 2840 0 0 {name=MN65
L=2u
W=2u
nf=1
m=1
ad="'int((nf+1)/2) * W/nf * 0.18u'"
pd="'2*int((nf+1)/2) * (W/nf + 0.18u)'"
as="'int((nf+2)/2) * W/nf * 0.18u'"
ps="'2*int((nf+2)/2) * (W/nf + 0.18u)'"
nrd="'0.18u / W'" nrs="'0.18u / W'"
sa=0 sb=0 sd=0
model=nfet_03v3
spiceprefix=X
}
C {symbols/nfet_03v3.sym} 190 2930 0 0 {name=MN66
L=2u
W=2u
nf=1
m=1
ad="'int((nf+1)/2) * W/nf * 0.18u'"
pd="'2*int((nf+1)/2) * (W/nf + 0.18u)'"
as="'int((nf+2)/2) * W/nf * 0.18u'"
ps="'2*int((nf+2)/2) * (W/nf + 0.18u)'"
nrd="'0.18u / W'" nrs="'0.18u / W'"
sa=0 sb=0 sd=0
model=nfet_03v3
spiceprefix=X
}
C {devices/lab_wire.sym} 70 2530 0 0 {name=p6 sig_type=std_logic lab=VB}
C {devices/lab_wire.sym} 150 2510 0 0 {name=p7 sig_type=std_logic lab=VG}
